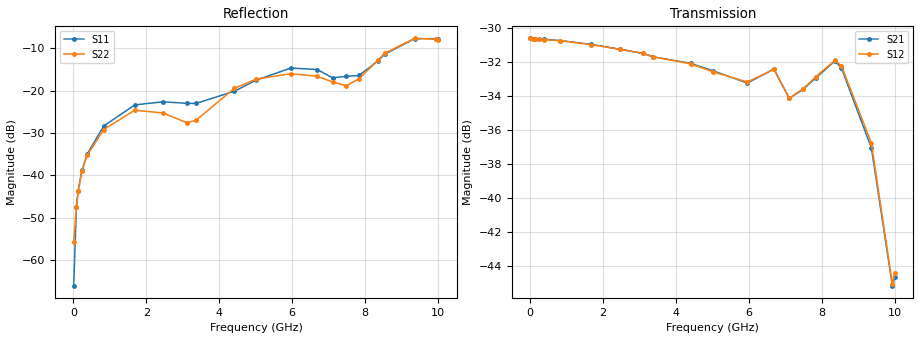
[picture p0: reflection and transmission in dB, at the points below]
! Device ID: PE43704
! Dir: z:\PE43704\PE43704_Char_1_20130516\PE43704\AMB\3p400V\29p75dB
! Serial: 14
! Insertion: A
! Impedance: 50 ohm
! Temp: Amb
! VDD: 3.400V
! Attenuation Step: 29.75dB
! IDD: 1.139731e-01mA
#  Hz  S  RI  R  50
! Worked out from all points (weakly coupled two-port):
!   401 points, 10 MHz to 10.01 GHz, reference 50 ohm
!   highest |S21| = -30.64 dB at 10 MHz (marker M1); lowest = -45.2 dB at 9.935 GHz (marker M2)
!   lowest |S11| = -66.0 dB at 10 MHz (marker M3), VSWR 1.00, Z = 50 + j0.0481 ohm
!   |S11| at or under -10 dB: start of sweep to 8.737 GHz
!   |S22| runs from -55.7 to -7.6 dB; largest |S21 - S12| = 0.00069
!   S11 on the Smith chart (normalised r, x): 10 MHz: 1.00, +0.00; 7.485 GHz: 0.78, +0.15; 8.535 GHz: 0.79, +0.45; 9.36 GHz: 0.54, +0.48; 10.01 GHz: 0.46, +0.27
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1e7  -0.000136 0.000481  0.0294 -7.66e-05  0.0294 -5.12e-05  -0.00158 0.000417
8.5e7  -6.54e-05 0.0043  0.0293 -0.000638  0.0293 -0.000617  -0.00146 0.004
1.35e8  -0.000297 0.00663  0.0293 -0.000991  0.0293 -0.000941  -0.00172 0.00626
2.35e8  -0.00194 0.0113  0.0292 -0.0017  0.0292 -0.00165  -0.00318 0.0108
3.85e8  -0.00504 0.0173  0.0291 -0.00275  0.029 -0.00269  -0.0062 0.0163
8.35e8  -0.0252 0.029  0.0284 -0.00564  0.0284 -0.00559  -0.0238 0.0255
1.685e9  -0.0664 0.0151  0.0261 -0.0107  0.0261 -0.0106  -0.0584 0.0083
2.46e9  -0.0738 -0.00624  0.0232 -0.0144  0.0232 -0.0144  -0.0542 -0.0069
3.11e9  -0.0708 -0.00657  0.0203 -0.0171  0.0203 -0.0171  -0.0418 0.00353
3.36e9  -0.0708 -0.00077  0.0189 -0.0178  0.0189 -0.0178  -0.043 0.0122
4.41e9  -0.0883 0.0437  0.0147 -0.02  0.0147 -0.0199  -0.0901 0.0571
5.01e9  -0.1121 0.0721  0.0124 -0.0201  0.0124 -0.0199  -0.1226 0.0613
5.96e9  -0.1592 0.0949  0.00823 -0.0201  0.0084 -0.0202  -0.1483 0.057
6.685e9  -0.1591 0.0802  0.00675 -0.0229  0.00666 -0.0229  -0.138 0.0546
7.11e9  -0.1284 0.061  0.00183 -0.0195  0.00211 -0.0195  -0.1061 0.0698
7.485e9  -0.1151 0.0933  0.00292 -0.0206  0.00286 -0.0207  -0.0764 0.0855
7.835e9  -0.0721 0.1333  0.0028 -0.0223  0.00275 -0.0225  -0.0611 0.1244
8.36e9  -0.0404 0.2234  -0.0051 -0.0247  -0.0051 -0.0248  -0.0775 0.2183
8.535e9  -0.0488 0.2654  -0.00809 -0.0227  -0.00803 -0.0231  -0.096 0.2594
9.36e9  -0.1877 0.3676  -0.0105 -0.00927  -0.0108 -0.00963  -0.2426 0.3373
9.935e9  -0.3126 0.2679  -0.00248 -0.00492  -0.0025 -0.00499  -0.3502 0.2033
1.001e10  -0.3242 0.241  -0.00108 -0.00575  -0.00156 -0.0058  -0.3587 0.1746
